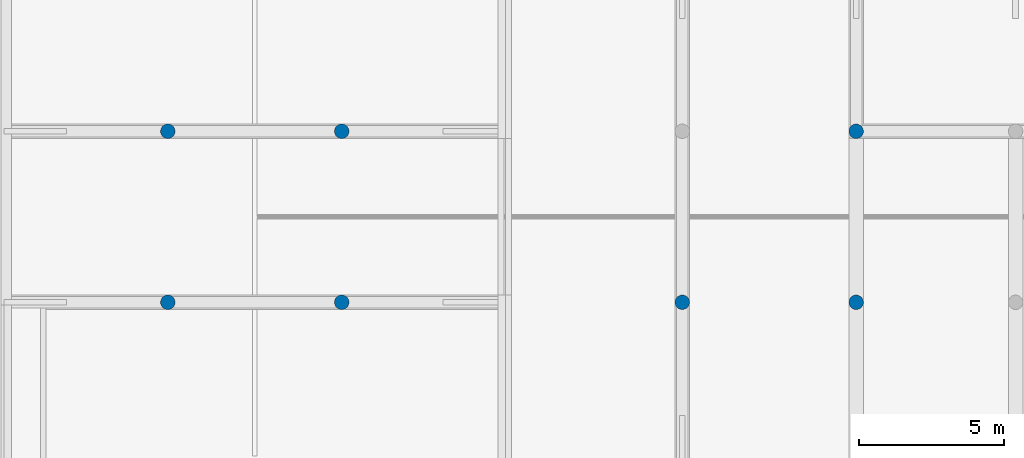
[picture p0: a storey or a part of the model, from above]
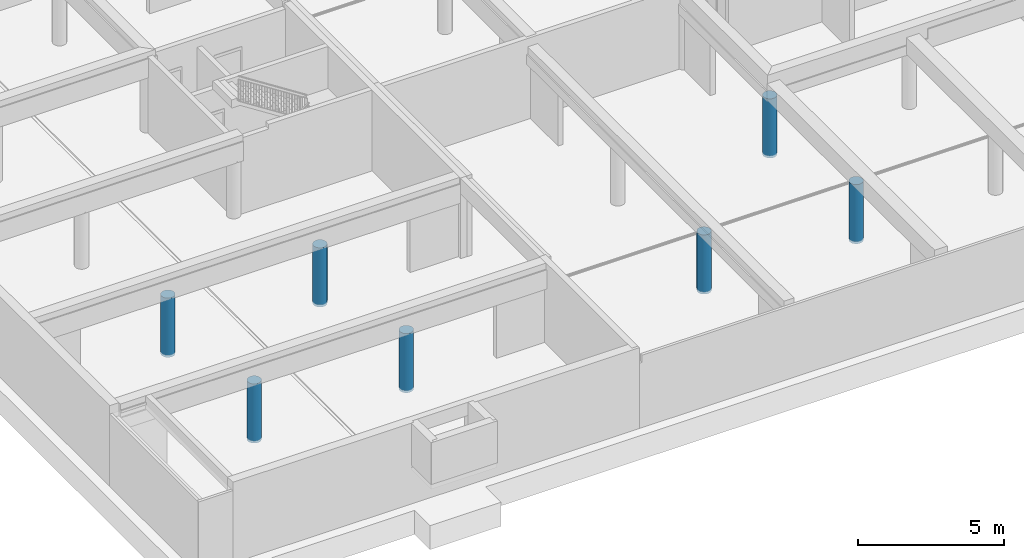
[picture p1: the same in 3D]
Properties of the parts of a building model (IFC2X3)

# File
Description: ViewDefinition [CoordinationView_V2.0], Option [Drawing Scale: 100.000000], Option [Elements to export: Visible elements (on all stories)], Option [Partial Structure Display: Entire Model], Option [IFC Domain: All], Option [Structural Function: All Elements], Option [Convert Grid elements: On], Option [Convert IFC Annotations and ARCHICAD 2D elements: Off], Option [Convert 2D symbols of Doors and Windows: Off], Option [Export geometries that Participates in Collision Detection only: Off], Option [Split complex elements: Off], Option [Material Preservation: Never explode], Option [Elements in Solid Element Operations: BRep], Option [Elements with junctions: BRep], Option [Slabs with slanted edge(s): BRep], Option [IFC Site Location: At Project Origin], Option [Curtain Wall export mode: Single Element], Option [Railing export mode: Single Element], Option [Stair export mode: Single Element], Option [Properties To Export: All properties], Option [Space containment: Off], Option [Bounding Box: Off], Option [Geometry to type objects: Off], Option [Element Properties: Off], Option [Building Material Properties: Off], Option [Element Parameters: Off], Option [Component Parameters: Off], Option [IFC Base Quantities: Off], Option [Door Window Parameters: On], Option [IFC Space boundaries: Off], Option [ARCHICAD Zone Categories as IFC Space classification data: Off], Option [Element Classifications: Off]
File name: C:\PROJEKTY\USTRONIE MORSKIE - Kulawiak\branze\09. Makieta\USTRONIE_7.1.ifc
Time: 2024-12-30T13:26:26
Author: mgr inż. arch. Mirosław Zwolski upr. nr BK IIF 7342/50/94
Organization: Building Designer Office
Written by: The EXPRESS Data Manager Version 5.02.0100.09 : 26 Sep 2013
Made in: IFC file generated by GRAPHISOFT ARCHICAD 23.0.0 POL FULL Windows version (IFC add-on version: 7000 POL FULL).
Authorization: mgr inż. arch. Mirosław Zwolski upr. nr BK IIF 7342/50/94

# IfcProject, BUDYNEK USŁUG TURYSTYCZNYCH
Description: BUDYNEK USŁUG TURYSTYCZNYCH WRAZ Z ZEWNĘTRZNĄ INSTALACJĄ GAZU, WEWNĘTRZNĄ LINIĄ ZASILANIA, INSTALACJĄ KANALIZACJI DESZCZOWEJ ORAZ PRZYŁĄCZAMI WODOCIĄGOWYM, KANALIZACJI SANITARNEJ I DESZCZOWEJ

# IfcSite, USTRONIE MORSKIE
Description: ul. NADBRZEŻNA 1 78-111 USTRONIE MORSKIE; RefLatitude: 54, 22, 0, 0; RefLongitude: 18, 40, 0, 0; RefElevation: 4500 mm

# IfcBuildingStorey (8)
In: Budynek
Name | Elevation (mm)
GARAZ | -3600
PARTER | 0
PIĘTRO 1 | 4000
PIĘTRO 2 | 7000
PIĘTRO 3 | 10000
PIĘTRO 4 | 13000
ANTRESOLA - KOND. TECHNICZNA | 16000
DACH | 19000

# IfcBeam: Beton konstrukcyjny 01 200 x 400 (3)
In: ANTRESOLA - KOND. TECHNICZNA
Material: Beton konstrukcyjny 01
Pset_BeamCommon - FireRating: -; Reference: Beton konstrukcyjny 01 200 x 400
Pset_ConcreteElementGeneral - FireRating: -; ConstructionType: -
Pset_FireRatingProperties - FireResistanceRating: -; IsCombustible: no
AC_Pset_RenovationAndPhasing - Renovation Status: New

# IfcBeam: Beton konstrukcyjny 01 200 x 500, B1
In: GARAZ
Material: Beton konstrukcyjny 01
Pset_BeamCommon - FireRating: -; Reference: Beton konstrukcyjny 01 200 x 500
Pset_ConcreteElementGeneral - FireRating: -; ConstructionType: -
Pset_FireRatingProperties - FireResistanceRating: -; IsCombustible: no
AC_Pset_RenovationAndPhasing - Renovation Status: New

# IfcBeam: Beton konstrukcyjny 01 200 x 550, B1
In: GARAZ
Material: Beton konstrukcyjny 01
Pset_BeamCommon - FireRating: -; Reference: Beton konstrukcyjny 01 200 x 550
Pset_ConcreteElementGeneral - FireRating: -; ConstructionType: -
Pset_FireRatingProperties - FireResistanceRating: -; IsCombustible: no
AC_Pset_RenovationAndPhasing - Renovation Status: New

# IfcBeam: Beton konstrukcyjny 01 200 x 650 (5)
In: GARAZ
Material: Beton konstrukcyjny 01
Pset_BeamCommon - FireRating: -; Reference: Beton konstrukcyjny 01 200 x 650
Pset_ConcreteElementGeneral - FireRating: -; ConstructionType: -
Pset_FireRatingProperties - FireResistanceRating: -; IsCombustible: no
AC_Pset_RenovationAndPhasing - Renovation Status: New

# IfcBeam: Beton konstrukcyjny 01 500 x 1000 (2)
In: GARAZ
Material: Beton konstrukcyjny 01
Pset_BeamCommon - FireRating: -; Reference: Beton konstrukcyjny 01 500 x 1000
Pset_ConcreteElementGeneral - FireRating: -; ConstructionType: -
Pset_FireRatingProperties - FireResistanceRating: -; IsCombustible: no
AC_Pset_RenovationAndPhasing - Renovation Status: New

# IfcBeam: Beton konstrukcyjny 01 500 x 700 (4)
In: GARAZ
Material: Beton konstrukcyjny 01
Pset_BeamCommon - FireRating: -; Reference: Beton konstrukcyjny 01 500 x 700
Pset_ConcreteElementGeneral - FireRating: -; ConstructionType: -
Pset_FireRatingProperties - FireResistanceRating: -; IsCombustible: no
AC_Pset_RenovationAndPhasing - Renovation Status: New

# IfcBeam: Beton konstrukcyjny B25 400 x 600 (2)
In: PARTER
Material: Beton konstrukcyjny B25
Pset_BeamCommon - FireRating: -; Reference: Beton konstrukcyjny B25 400 x 600
Pset_ConcreteElementGeneral - FireRating: -; ConstructionType: -
Pset_FireRatingProperties - FireResistanceRating: -; IsCombustible: no
AC_Pset_RenovationAndPhasing - Renovation Status: New

# IfcBeam: GARAŻ P01 500 x 1050 (20)
In: GARAZ
Material: Termoizolacja WEŁNA SKALNA, Beton konstrukcyjny 01
Pset_BeamCommon - FireRating: -; Reference: GARAŻ P01 500 x 1050
Pset_ConcreteElementGeneral - FireRating: -; ConstructionType: -
Pset_FireRatingProperties - FireResistanceRating: -; IsCombustible: no
AC_Pset_RenovationAndPhasing - Renovation Status: New

# IfcBeam: GARAŻ P02 500 x 700 (2)
In: GARAZ
Material: Termoizolacja WEŁNA SKALNA, Beton konstrukcyjny 01
Pset_BeamCommon - FireRating: -; Reference: GARAŻ P02 500 x 700
Pset_ConcreteElementGeneral - FireRating: -; ConstructionType: -
Pset_FireRatingProperties - FireResistanceRating: -; IsCombustible: no
AC_Pset_RenovationAndPhasing - Renovation Status: New

# IfcBeam: Laminat 50 x 250 (11)
In: DACH
Material: Laminat
Pset_BeamCommon - FireRating: -; Reference: Laminat 50 x 250
Pset_ConcreteElementGeneral - FireRating: -; ConstructionType: -
Pset_FireRatingProperties - FireResistanceRating: -; IsCombustible: no
AC_Pset_RenovationAndPhasing - Renovation Status: New

# IfcBeam: USTR - balkon_01 1850 x 570 (6)
In: PIĘTRO 1
Material: Laminat, Membrana przeciwwilgociowa, Blacha ocynkowana, Beton konstrukcyjny B25, Płyty styropianowe twarde HIGH-PRIORITY
Pset_BeamCommon - FireRating: -; Reference: USTR - balkon_01 1850 x 570
Pset_ConcreteElementGeneral - FireRating: -; ConstructionType: -
Pset_FireRatingProperties - FireResistanceRating: -; IsCombustible: no
AC_Pset_RenovationAndPhasing - Renovation Status: New
Name
3 x P7
3 x B1

# IfcBeam: USTR - balkon_02 1810 x 320 (18)
Material: Laminat, Membrana przeciwwilgociowa, Blacha ocynkowana, Beton konstrukcyjny B25, Płyty styropianowe twarde HIGH-PRIORITY
Pset_BeamCommon - FireRating: -; Reference: USTR - balkon_02 1810 x 320
Pset_ConcreteElementGeneral - FireRating: -; ConstructionType: -
Pset_FireRatingProperties - FireResistanceRating: -; IsCombustible: no
AC_Pset_RenovationAndPhasing - Renovation Status: New
Name | In
2 x B1 | PIĘTRO 2
4 x P8 | PIĘTRO 2
2 x B1 | PIĘTRO 3
4 x P8 | PIĘTRO 3
4 x P8 | PIĘTRO 4
2 x B1 | PIĘTRO 4

# IfcBeam: Własny Profil 50 x 250 (11)
In: DACH
Material: Laminat
Pset_BeamCommon - FireRating: -; Reference: Własny Profil 50 x 250
Pset_ConcreteElementGeneral - FireRating: -; ConstructionType: -
Pset_FireRatingProperties - FireResistanceRating: -; IsCombustible: no
AC_Pset_RenovationAndPhasing - Renovation Status: New

# IfcBuildingElementProxy (16)
AC_Pset_RenovationAndPhasing - Renovation Status: New
Name | In
Obiekt-007 | GARAZ
2 x Obiekt-007 | PARTER
2 x Obiekt-007 | PIĘTRO 1
2 x Obiekt-007 | PIĘTRO 2
2 x Obiekt-007 | PIĘTRO 3
2 x Obiekt-007 | PIĘTRO 4
2 x Obiekt-007 | ANTRESOLA - KOND. TECHNICZNA
3 x Obiekt-007 | DACH

# IfcBuildingElementProxy: 12+10 kominy 230 (163)
Pset_ConcreteElementGeneral - EnvironmentalClass: Brak
AC_Pset_RenovationAndPhasing - Renovation Status: New
Name | In | Material
2 x Œciana-006 | ANTRESOLA - KOND. TECHNICZNA | Bloczki silikatowe, Wełna ELEW, Tynk zewnętrzny
2 x Œciana-006 | ANTRESOLA - KOND. TECHNICZNA | Tynk zewnętrzny, Wełna ELEW, Bloczki silikatowe
86 x Œciana-006 | DACH | Bloczki silikatowe, Wełna ELEW, Tynk zewnętrzny
73 x Œciana-006 | DACH | Tynk zewnętrzny, Wełna ELEW, Bloczki silikatowe

# IfcBuildingElementProxy: 12+18_TERMO 310 (18)
Pset_ConcreteElementGeneral - EnvironmentalClass: Brak
AC_Pset_RenovationAndPhasing - Renovation Status: New
Name | In | Material
3 x Œciana-006 | ANTRESOLA - KOND. TECHNICZNA | Tynk zewnętrzny, Wełna ELEW, Bloczki silikatowe
3 x Œciana-006 | ANTRESOLA - KOND. TECHNICZNA | Bloczki silikatowe, Wełna ELEW, Tynk zewnętrzny
6 x Œciana-006 | DACH | Bloczki silikatowe, Wełna ELEW, Tynk zewnętrzny
6 x Œciana-006 | DACH | Tynk zewnętrzny, Wełna ELEW, Bloczki silikatowe

# IfcBuildingElementProxy: 12+20 330 (16)
Pset_ConcreteElementGeneral - EnvironmentalClass: Brak
AC_Pset_RenovationAndPhasing - Renovation Status: New
Name | In | Material
6 x Ściana-009 | ANTRESOLA - KOND. TECHNICZNA | Tynk zewnętrzny, Wełna ELEW, Bloczki silikatowe
6 x Ściana-009 | ANTRESOLA - KOND. TECHNICZNA | Bloczki silikatowe, Wełna ELEW, Tynk zewnętrzny
3 x Œciana-006 | DACH | Bloczki silikatowe, Wełna ELEW, Tynk zewnętrzny
Œciana-006 | DACH | Tynk zewnętrzny, Wełna ELEW, Bloczki silikatowe

# IfcBuildingElementProxy: 15+15 AKU 300, Œciana-007
In: ANTRESOLA - KOND. TECHNICZNA
Material: Wełna ELEW, Bloczki silikatowe
Pset_ConcreteElementGeneral - EnvironmentalClass: Brak
AC_Pset_RenovationAndPhasing - Renovation Status: New

# IfcBuildingElementProxy: 15+2xTYNK 170 (4)
In: ANTRESOLA - KOND. TECHNICZNA
Material: Tynk wewnętrzny (2), Beton konstrukcyjny B25
Pset_ConcreteElementGeneral - EnvironmentalClass: Brak
AC_Pset_RenovationAndPhasing - Renovation Status: New

# IfcBuildingElementProxy: 16+15 AKU 310 (7)
In: ANTRESOLA - KOND. TECHNICZNA
Pset_ConcreteElementGeneral - EnvironmentalClass: Brak
AC_Pset_RenovationAndPhasing - Renovation Status: New
Name | Material
Œciana-006 | Beton konstrukcyjny B25, Izolacja akustyczna
3 x Œciana-007 | Beton konstrukcyjny B25, Izolacja akustyczna
Œciana-006 | Izolacja akustyczna, Beton konstrukcyjny B25
2 x Œciana-007 | Izolacja akustyczna, Beton konstrukcyjny B25

# IfcBuildingElementProxy: 16+20 370 (2)
In: ANTRESOLA - KOND. TECHNICZNA
Pset_ConcreteElementGeneral - EnvironmentalClass: Brak
AC_Pset_RenovationAndPhasing - Renovation Status: New
Name | Material
SZ-01 | Tynk zewnętrzny, Wełna ELEW, Beton konstrukcyjny B25
SZ-01 | Beton konstrukcyjny B25, Wełna ELEW, Tynk zewnętrzny

# IfcBuildingElementProxy: 18 SILIKAT+-10 290 (7)
In: DACH
Pset_ConcreteElementGeneral - EnvironmentalClass: Brak
AC_Pset_RenovationAndPhasing - Renovation Status: New
Name | Material
4 x Œciana-006 | Tynk zewnętrzny, Wełna ELEW, Bloczki silikatowe
3 x Œciana-006 | Bloczki silikatowe, Wełna ELEW, Tynk zewnętrzny

# IfcBuildingElementProxy: 18 SILIKAT+20 390 (19)
In: DACH
Pset_ConcreteElementGeneral - EnvironmentalClass: Brak
AC_Pset_RenovationAndPhasing - Renovation Status: New
Name | Material
7 x Œciana-006 | Bloczki silikatowe, Wełna ELEW, Tynk zewnętrzny
10 x Œciana-006 | Tynk zewnętrzny, Wełna ELEW, Bloczki silikatowe
SZ-01 | Tynk zewnętrzny, Wełna ELEW, Bloczki silikatowe
SZ-01 | Bloczki silikatowe, Wełna ELEW, Tynk zewnętrzny

# IfcBuildingElementProxy: 18 SILIKAT+20-10 500 (47)
Material: Tynk zewnętrzny (2), Wełna ELEW (2), Bloczki silikatowe
Pset_ConcreteElementGeneral - EnvironmentalClass: Brak
AC_Pset_RenovationAndPhasing - Renovation Status: New
Name | In
14 x Œciana-006 | ANTRESOLA - KOND. TECHNICZNA
33 x Œciana-006 | DACH

# IfcBuildingElementProxy: 18 SILKA +5 AKU 255 (2)
In: PARTER
Pset_ConcreteElementGeneral - EnvironmentalClass: Brak
AC_Pset_RenovationAndPhasing - Renovation Status: New
Name | Material
SW-02 | Płyta GK, Izolacja akustyczna, Bloczki silikatowe
SW-02 | Bloczki silikatowe, Izolacja akustyczna, Płyta GK

# IfcBuildingElementProxy: 18+15 AKU 340 (16)
In: ANTRESOLA - KOND. TECHNICZNA
Pset_ConcreteElementGeneral - EnvironmentalClass: Brak
AC_Pset_RenovationAndPhasing - Renovation Status: New
Name | Material
7 x Œciana-006 | Tynk zewnętrzny, Wełna ELEW, Bloczki silikatowe
7 x Œciana-006 | Bloczki silikatowe, Wełna ELEW, Tynk zewnętrzny
2 x Œciana-007 | Tynk zewnętrzny, Wełna ELEW, Bloczki silikatowe

# IfcBuildingElementProxy: 20+10 300 (6)
Pset_ConcreteElementGeneral - EnvironmentalClass: Brak
AC_Pset_RenovationAndPhasing - Renovation Status: New
Name | In | Material
Œciana-006 | GARAZ | Płyty styropianowe twarde, Beton konstrukcyjny B25
Œciana-006 | PARTER | Płyty styropianowe twarde, Beton konstrukcyjny B25
Œciana-007 | DACH | Płyty styropianowe twarde, Beton konstrukcyjny B25
2 x Œciana-007 | DACH | Beton konstrukcyjny B25, Płyty styropianowe twarde
Œciana-008 | DACH | Płyty styropianowe twarde, Beton konstrukcyjny B25

# IfcBuildingElementProxy: 20+10 GARAŻ 310 (19)
Pset_ConcreteElementGeneral - EnvironmentalClass: Brak
AC_Pset_RenovationAndPhasing - Renovation Status: New
Name | In | Material
5 x Œciana-006 | GARAZ | Membrana przeciwwilgociowa, Płyty styropianowe twarde HIGH-PRIORITY, Beton konstrukcyjny 01
5 x Œciana-006 | GARAZ | Beton konstrukcyjny 01, Płyty styropianowe twarde HIGH-PRIORITY, Membrana przeciwwilgociowa
5 x Œciana-006 | PARTER | Beton konstrukcyjny 01, Płyty styropianowe twarde HIGH-PRIORITY, Membrana przeciwwilgociowa
4 x Œciana-006 | PARTER | Membrana przeciwwilgociowa, Płyty styropianowe twarde HIGH-PRIORITY, Beton konstrukcyjny 01

# IfcBuildingElementProxy: 20+15 360, SZ-02
In: PARTER
Material: Beton konstrukcyjny B25, Wełna ELEW, Tynk zewnętrzny
Pset_ConcreteElementGeneral - EnvironmentalClass: Brak
AC_Pset_RenovationAndPhasing - Renovation Status: New

# IfcBuildingElementProxy: 20+20 410 (160)
Pset_ConcreteElementGeneral - EnvironmentalClass: Brak
AC_Pset_RenovationAndPhasing - Renovation Status: New
Name | In | Material
SZ-01 | GARAZ | Beton konstrukcyjny B25, Wełna ELEW, Tynk zewnętrzny
17 x SZ-01 | PARTER | Beton konstrukcyjny B25, Wełna ELEW, Tynk zewnętrzny
5 x SZ-01 | PARTER | Tynk zewnętrzny, Wełna ELEW, Beton konstrukcyjny B25
13 x SZ-01 | PIĘTRO 1 | Beton konstrukcyjny B25, Wełna ELEW, Tynk zewnętrzny
11 x SZ-01 | PIĘTRO 1 | Tynk zewnętrzny, Wełna ELEW, Beton konstrukcyjny B25
11 x SZ-01 | PIĘTRO 2 | Tynk zewnętrzny, Wełna ELEW, Beton konstrukcyjny B25
14 x SZ-01 | PIĘTRO 2 | Beton konstrukcyjny B25, Wełna ELEW, Tynk zewnętrzny
13 x SZ-01 | PIĘTRO 3 | Beton konstrukcyjny B25, Wełna ELEW, Tynk zewnętrzny
11 x SZ-01 | PIĘTRO 3 | Tynk zewnętrzny, Wełna ELEW, Beton konstrukcyjny B25
13 x SZ-01 | PIĘTRO 4 | Beton konstrukcyjny B25, Wełna ELEW, Tynk zewnętrzny
11 x SZ-01 | PIĘTRO 4 | Tynk zewnętrzny, Wełna ELEW, Beton konstrukcyjny B25
9 x SZ-01 | ANTRESOLA - KOND. TECHNICZNA | Beton konstrukcyjny B25, Wełna ELEW, Tynk zewnętrzny
11 x SZ-01 | ANTRESOLA - KOND. TECHNICZNA | Tynk zewnętrzny, Wełna ELEW, Beton konstrukcyjny B25
6 x Œciana-006 | ANTRESOLA - KOND. TECHNICZNA | Beton konstrukcyjny B25, Wełna ELEW, Tynk zewnętrzny
5 x Œciana-006 | ANTRESOLA - KOND. TECHNICZNA | Tynk zewnętrzny, Wełna ELEW, Beton konstrukcyjny B25
Œciana-008 | ANTRESOLA - KOND. TECHNICZNA | Tynk zewnętrzny, Wełna ELEW, Beton konstrukcyjny B25
4 x Œciana-006 | DACH | Tynk zewnętrzny, Wełna ELEW, Beton konstrukcyjny B25
2 x SZ-01 | DACH | Tynk zewnętrzny, Wełna ELEW, Beton konstrukcyjny B25
2 x SZ-01 | DACH | Beton konstrukcyjny B25, Wełna ELEW, Tynk zewnętrzny

# IfcBuildingElementProxy: 20+20 HP 410 (4)
In: PARTER
Pset_ConcreteElementGeneral - EnvironmentalClass: Brak
AC_Pset_RenovationAndPhasing - Renovation Status: New
Name | Material
SZ-01 | Beton konstrukcyjny B25, Wełna ELEW wysoki priorytet, Tynk zewnętrzny
3 x SZ-01 | Tynk zewnętrzny, Wełna ELEW wysoki priorytet, Beton konstrukcyjny B25

# IfcBuildingElementProxy: 20+20-10 520 (2)
In: ANTRESOLA - KOND. TECHNICZNA
Material: Tynk zewnętrzny (2), Wełna ELEW (2), Beton konstrukcyjny B25
Pset_ConcreteElementGeneral - EnvironmentalClass: Brak
AC_Pset_RenovationAndPhasing - Renovation Status: New

# IfcBuildingElementProxy: 20+20-5 470 (6)
Material: Tynk zewnętrzny (2), Wełna ELEW (2), Beton konstrukcyjny B25
Pset_ConcreteElementGeneral - EnvironmentalClass: Brak
AC_Pset_RenovationAndPhasing - Renovation Status: New
Name | In
2 x Œciana-007 | PIĘTRO 4
2 x Œciana-006 | ANTRESOLA - KOND. TECHNICZNA
2 x Œciana-007 | ANTRESOLA - KOND. TECHNICZNA

# IfcBuildingElementProxy: 20+5 250 (8)
In: GARAZ
Pset_ConcreteElementGeneral - EnvironmentalClass: Brak
AC_Pset_RenovationAndPhasing - Renovation Status: New
Name | Material
2 x Œciana-008 | Płyty styropianowe twarde, Beton konstrukcyjny 01
Œciana-007 | Beton konstrukcyjny 01, Płyty styropianowe twarde
3 x Œciana-006 | Płyty styropianowe twarde, Beton konstrukcyjny 01
Œciana-007 | Płyty styropianowe twarde, Beton konstrukcyjny 01
SW-01 | Beton konstrukcyjny 01, Płyty styropianowe twarde

# IfcBuildingElementProxy: 20+5 AKU 275 (40)
Pset_ConcreteElementGeneral - EnvironmentalClass: Brak
AC_Pset_RenovationAndPhasing - Renovation Status: New
Name | In | Material
2 x SW-01 | PARTER | Beton konstrukcyjny B25, Izolacja akustyczna, Płyta GK
2 x SW-01 | PARTER | Płyta GK, Izolacja akustyczna, Beton konstrukcyjny B25
Œciana-007 | PARTER | Płyta GK, Izolacja akustyczna, Beton konstrukcyjny B25
Œciana-007 | PARTER | Beton konstrukcyjny B25, Izolacja akustyczna, Płyta GK
SW-01 | PIĘTRO 1 | Płyta GK, Izolacja akustyczna, Beton konstrukcyjny B25
3 x Œciana-007 | PIĘTRO 1 | Beton konstrukcyjny B25, Izolacja akustyczna, Płyta GK
SW-01 | PIĘTRO 1 | Beton konstrukcyjny B25, Izolacja akustyczna, Płyta GK
2 x Œciana-007 | PIĘTRO 1 | Płyta GK, Izolacja akustyczna, Beton konstrukcyjny B25
2 x Œciana-007 | PIĘTRO 2 | Płyta GK, Izolacja akustyczna, Beton konstrukcyjny B25
3 x Œciana-007 | PIĘTRO 2 | Beton konstrukcyjny B25, Izolacja akustyczna, Płyta GK
SW-01 | PIĘTRO 2 | Beton konstrukcyjny B25, Izolacja akustyczna, Płyta GK
SW-01 | PIĘTRO 2 | Płyta GK, Izolacja akustyczna, Beton konstrukcyjny B25
3 x Œciana-007 | PIĘTRO 3 | Beton konstrukcyjny B25, Izolacja akustyczna, Płyta GK
2 x Œciana-007 | PIĘTRO 3 | Płyta GK, Izolacja akustyczna, Beton konstrukcyjny B25
SW-01 | PIĘTRO 3 | Beton konstrukcyjny B25, Izolacja akustyczna, Płyta GK
SW-01 | PIĘTRO 3 | Płyta GK, Izolacja akustyczna, Beton konstrukcyjny B25
SW-01 | PIĘTRO 4 | Płyta GK, Izolacja akustyczna, Beton konstrukcyjny B25
3 x Œciana-007 | PIĘTRO 4 | Beton konstrukcyjny B25, Izolacja akustyczna, Płyta GK
2 x Œciana-007 | PIĘTRO 4 | Płyta GK, Izolacja akustyczna, Beton konstrukcyjny B25
SW-01 | PIĘTRO 4 | Beton konstrukcyjny B25, Izolacja akustyczna, Płyta GK
2 x SW-01 | ANTRESOLA - KOND. TECHNICZNA | Beton konstrukcyjny B25, Izolacja akustyczna, Płyta GK
Œciana-007 | ANTRESOLA - KOND. TECHNICZNA | Beton konstrukcyjny B25, Izolacja akustyczna, Płyta GK
2 x SW-01 | ANTRESOLA - KOND. TECHNICZNA | Płyta GK, Izolacja akustyczna, Beton konstrukcyjny B25
Œciana-006 | ANTRESOLA - KOND. TECHNICZNA | Płyta GK, Izolacja akustyczna, Beton konstrukcyjny B25

# IfcBuildingElementProxy: 20+8+2 320 (4)
In: PARTER
Pset_ConcreteElementGeneral - EnvironmentalClass: Brak
AC_Pset_RenovationAndPhasing - Renovation Status: New
Name | Material
3 x Œciana-006 | Laminat, Płyty styropianowe twarde, Beton konstrukcyjny B25
Œciana-006 | Beton konstrukcyjny B25, Płyty styropianowe twarde, Laminat

# IfcBuildingElementProxy: 25+10 GARAŻ 360 (13)
In: GARAZ
Pset_ConcreteElementGeneral - EnvironmentalClass: Brak
AC_Pset_RenovationAndPhasing - Renovation Status: New
Name | Material
6 x SZ-02 | Beton konstrukcyjny 01, Płyty styropianowe twarde HIGH-PRIORITY, Membrana przeciwwilgociowa
7 x SZ-02 | Membrana przeciwwilgociowa, Płyty styropianowe twarde HIGH-PRIORITY, Beton konstrukcyjny 01

# IfcBuildingElementProxy: 330-SD GK 2-warstwy 75 (299)
Pset_ConcreteElementGeneral - EnvironmentalClass: Brak
AC_Pset_RenovationAndPhasing - Renovation Status: New
Name | In | Material
29 x Ściana-009 | PARTER | Płyta GK (2), -Pustka powietrzna
22 x Ściana-009 | PARTER | -Pustka powietrzna, Płyta GK (2)
32 x Ściana-009 | PIĘTRO 1 | -Pustka powietrzna, Płyta GK (2)
32 x Ściana-009 | PIĘTRO 1 | Płyta GK (2), -Pustka powietrzna
32 x Ściana-009 | PIĘTRO 2 | -Pustka powietrzna, Płyta GK (2)
32 x Ściana-009 | PIĘTRO 2 | Płyta GK (2), -Pustka powietrzna
30 x Ściana-009 | PIĘTRO 3 | Płyta GK (2), -Pustka powietrzna
32 x Ściana-009 | PIĘTRO 3 | -Pustka powietrzna, Płyta GK (2)
29 x Ściana-009 | PIĘTRO 4 | Płyta GK (2), -Pustka powietrzna
29 x Ściana-009 | PIĘTRO 4 | -Pustka powietrzna, Płyta GK (2)

# IfcBuildingElementProxy: BALKON bok 01 520 (52)
Material: Tynk zewnętrzny (2), Wełna ELEW (2), Beton konstrukcyjny B25
Pset_ConcreteElementGeneral - EnvironmentalClass: Brak
AC_Pset_RenovationAndPhasing - Renovation Status: New
Name | In
12 x Œciana-006 | PIĘTRO 1
12 x Œciana-006 | PIĘTRO 2
12 x Œciana-006 | PIĘTRO 3
12 x Œciana-006 | PIĘTRO 4
2 x Œciana-007 | ANTRESOLA - KOND. TECHNICZNA
2 x Œciana-006 | ANTRESOLA - KOND. TECHNICZNA

# IfcBuildingElementProxy: BALKON bok 04 220 (4)
In: ANTRESOLA - KOND. TECHNICZNA
Material: Tynk zewnętrzny (2), Bloczki silikatowe
Pset_ConcreteElementGeneral - EnvironmentalClass: Brak
AC_Pset_RenovationAndPhasing - Renovation Status: New

# IfcBuildingElementProxy: Beton konstrukcyjny 01 200 (71)
In: GARAZ
Material: Beton konstrukcyjny 01
Pset_ConcreteElementGeneral - EnvironmentalClass: Brak
AC_Pset_RenovationAndPhasing - Renovation Status: New
Name
68 x SW-01
2 x SW-02
Œciana-007

# IfcBuildingElementProxy: Beton konstrukcyjny 01 250, Œciana-008
In: GARAZ
Material: Beton konstrukcyjny 01
Pset_ConcreteElementGeneral - EnvironmentalClass: Brak
AC_Pset_RenovationAndPhasing - Renovation Status: New

# IfcBuildingElementProxy: Beton konstrukcyjny B25 160 (86)
Material: Beton konstrukcyjny B25
Pset_ConcreteElementGeneral - EnvironmentalClass: Brak
AC_Pset_RenovationAndPhasing - Renovation Status: New
Name | In
19 x SW-01 | PARTER
16 x SW-01 | PIĘTRO 1
16 x SW-01 | PIĘTRO 2
16 x SW-01 | PIĘTRO 3
13 x SW-01 | PIĘTRO 4
5 x SW-01 | ANTRESOLA - KOND. TECHNICZNA
SZ-01 | ANTRESOLA - KOND. TECHNICZNA

# IfcBuildingElementProxy: Beton konstrukcyjny B25 180, SW-01
In: ANTRESOLA - KOND. TECHNICZNA
Material: Beton konstrukcyjny B25
Pset_ConcreteElementGeneral - EnvironmentalClass: Brak
AC_Pset_RenovationAndPhasing - Renovation Status: New

# IfcBuildingElementProxy: Beton konstrukcyjny B25 200 (401)
Material: Beton konstrukcyjny B25
Pset_ConcreteElementGeneral - EnvironmentalClass: Brak
AC_Pset_RenovationAndPhasing - Renovation Status: New
Name | In
71 x SW-01 | PARTER
71 x SW-01 | PIĘTRO 1
71 x SW-01 | PIĘTRO 2
67 x SW-01 | PIĘTRO 3
68 x SW-01 | PIĘTRO 4
47 x SW-01 | ANTRESOLA - KOND. TECHNICZNA
Œciana-006 | ANTRESOLA - KOND. TECHNICZNA
2 x SZ-01 | ANTRESOLA - KOND. TECHNICZNA
3 x SW-01 | DACH

# IfcBuildingElementProxy: Beton konstrukcyjny B25 450 (2)
In: ANTRESOLA - KOND. TECHNICZNA
Material: Beton konstrukcyjny B25
Pset_ConcreteElementGeneral - EnvironmentalClass: Brak
AC_Pset_RenovationAndPhasing - Renovation Status: New

# IfcBuildingElementProxy: Bloczki silikatowe 120 (796)
Material: Bloczki silikatowe
Pset_ConcreteElementGeneral - EnvironmentalClass: Brak
AC_Pset_RenovationAndPhasing - Renovation Status: New
Name | In
3 x SW-04 | GARAZ
126 x SW-04 | PARTER
9 x Ściana-010 | PARTER
2 x Œciana-007 | PARTER
148 x SW-04 | PIĘTRO 1
148 x SW-04 | PIĘTRO 2
150 x SW-04 | PIĘTRO 3
140 x SW-04 | PIĘTRO 4
4 x Ściana-009 | PIĘTRO 4
62 x SW-04 | ANTRESOLA - KOND. TECHNICZNA
4 x Ściana-009 | ANTRESOLA - KOND. TECHNICZNA

# IfcBuildingElementProxy: Bloczki silikatowe 150 (633)
Material: Bloczki silikatowe
Pset_ConcreteElementGeneral - EnvironmentalClass: Brak
AC_Pset_RenovationAndPhasing - Renovation Status: New
Name | In
12 x SW-04 | PARTER
48 x SW-03 | PARTER
22 x Ściana-009 | PARTER
6 x Œciana-007 | PARTER
28 x Ściana-009 | PIĘTRO 1
67 x SW-03 | PIĘTRO 1
10 x SW-04 | PIĘTRO 1
4 x Œciana-007 | PIĘTRO 1
71 x SW-03 | PIĘTRO 2
10 x SW-04 | PIĘTRO 2
24 x Ściana-009 | PIĘTRO 2
4 x Œciana-007 | PIĘTRO 2
101 x SW-03 | PIĘTRO 3
8 x Ściana-009 | PIĘTRO 3
4 x Ściana-010 | PIĘTRO 3
4 x Œciana-007 | PIĘTRO 3
117 x SW-03 | PIĘTRO 4
4 x Ściana-009 | PIĘTRO 4
4 x Œciana-007 | PIĘTRO 4
78 x SW-03 | ANTRESOLA - KOND. TECHNICZNA
5 x SW-04 | ANTRESOLA - KOND. TECHNICZNA
2 x SW-02 | ANTRESOLA - KOND. TECHNICZNA

# IfcBuildingElementProxy: Bloczki silikatowe 180 (137)
Material: Bloczki silikatowe
Pset_ConcreteElementGeneral - EnvironmentalClass: Brak
AC_Pset_RenovationAndPhasing - Renovation Status: New
Name | In
18 x SW-02 | PARTER
23 x SW-02 | PIĘTRO 1
24 x SW-02 | PIĘTRO 2
21 x SW-02 | PIĘTRO 3
18 x SW-02 | PIĘTRO 4
2 x Œciana-007 | PIĘTRO 4
29 x SW-02 | ANTRESOLA - KOND. TECHNICZNA
2 x Œciana-006 | ANTRESOLA - KOND. TECHNICZNA

# IfcBuildingElementProxy: Bloczki silikatowe 200 (6)
Material: Bloczki silikatowe
Pset_ConcreteElementGeneral - EnvironmentalClass: Brak
AC_Pset_RenovationAndPhasing - Renovation Status: New
Name | In
2 x SW-01 | PARTER
4 x SW-01 | ANTRESOLA - KOND. TECHNICZNA

# IfcBuildingElementProxy: Bloczki silikatowe 240, Œciana-006
In: PARTER
Material: Bloczki silikatowe
Pset_ConcreteElementGeneral - EnvironmentalClass: Brak
AC_Pset_RenovationAndPhasing - Renovation Status: New

# IfcBuildingElementProxy: Bloczki silikatowe 40 (2)
In: PARTER
Material: Bloczki silikatowe
Pset_ConcreteElementGeneral - EnvironmentalClass: Brak
AC_Pset_RenovationAndPhasing - Renovation Status: New

# IfcBuildingElementProxy: Bloczki silikatowe 80 (152)
Material: Bloczki silikatowe
Pset_ConcreteElementGeneral - EnvironmentalClass: Brak
AC_Pset_RenovationAndPhasing - Renovation Status: New
Name | In
12 x Ściana-010 | PARTER
12 x Ściana-009 | PARTER
8 x Œciana-007 | PARTER
16 x Ściana-010 | PIĘTRO 1
14 x Ściana-009 | PIĘTRO 1
14 x Ściana-009 | PIĘTRO 2
16 x Ściana-010 | PIĘTRO 2
13 x Ściana-009 | PIĘTRO 3
15 x Ściana-010 | PIĘTRO 3
2 x Œciana-007 | PIĘTRO 3
14 x Ściana-009 | PIĘTRO 4
16 x Ściana-010 | PIĘTRO 4

# IfcBuildingElementProxy: Drzwi 23 (531)
Pset_ConcreteElementGeneral - EnvironmentalClass: Brak
Pset_PrecastConcreteElementGeneral - SerialNumber: -
Pset_ManufacturerOccurrence - BarCode: -
Pset_ManufacturerTypeInformation - ModelLabel: -
AC_Pset_RenovationAndPhasing - Renovation Status: New
Name | In | FireRating = FireResistanceRating
4 x Dw01 | GARAZ | EI 30
6 x Dw02 | GARAZ | EI 60
3 x Dw03 | GARAZ | EI 30
30 x Dw.1 | PARTER | EI 30
33 x Dw.4 | PARTER | nd.
18 x Dw.3 | PARTER | nd
7 x Dw.2 | PARTER | EI 60
Dw.4' | PARTER | nd.
Dw.1' | PARTER | EIS 30
2 x Dw.2S | PARTER | EIS 60
 | PARTER
Syst. | PARTER
37 x Dw.4 | PIĘTRO 1 | nd.
24 x Dw.3 | PIĘTRO 1 | nd
38 x Dw.1 | PIĘTRO 1 | EI 30
7 x Dw.2 | PIĘTRO 1 | EI 60
Dw.4' | PIĘTRO 1 | nd.
Dw.1' | PIĘTRO 1 | EIS 30
37 x Dw.4 | PIĘTRO 2 | nd.
38 x Dw.1 | PIĘTRO 2 | EI 30
24 x Dw.3 | PIĘTRO 2 | nd
7 x Dw.2 | PIĘTRO 2 | EI 60
Dw.4' | PIĘTRO 2 | nd.
Dw.1' | PIĘTRO 2 | EIS 30
35 x Dw.4 | PIĘTRO 3 | nd.
36 x Dw.1 | PIĘTRO 3 | EI 30
30 x Dw.3 | PIĘTRO 3 | nd
Dw.1' | PIĘTRO 3 | EIS 30
7 x Dw.2 | PIĘTRO 3 | EI 60
Dw.4' | PIĘTRO 3 | nd.
36 x Dw.4 | PIĘTRO 4 | nd.
9 x Dw.3 | PIĘTRO 4 | nd
5 x Dw.2 | PIĘTRO 4 | EI 60
36 x Dw.1 | PIĘTRO 4 | EI 30
3 x Dw.03 | PIĘTRO 4
Dw.1' | PIĘTRO 4 | EIS 30
2 x  | ANTRESOLA - KOND. TECHNICZNA | EIS 60
2 x D8 | ANTRESOLA - KOND. TECHNICZNA | EI 60
Dw.01 | ANTRESOLA - KOND. TECHNICZNA | EIS 30
2 x Dw.02 | ANTRESOLA - KOND. TECHNICZNA | EI 30
D9 | ANTRESOLA - KOND. TECHNICZNA | EI 60

# IfcBuildingElementProxy: Drzwi garażowe, segmentowe 23, B01
In: GARAZ
Pset_ConcreteElementGeneral - EnvironmentalClass: Brak
Pset_PrecastConcreteElementGeneral - SerialNumber: -
Pset_ManufacturerOccurrence - BarCode: -
Pset_ManufacturerTypeInformation - ModelLabel: -
AC_Pset_RenovationAndPhasing - Renovation Status: New

# IfcBuildingElementProxy: Drzwi podwójne 23 (62)
Pset_ConcreteElementGeneral - EnvironmentalClass: Brak
Pset_PrecastConcreteElementGeneral - SerialNumber: -
Pset_ManufacturerOccurrence - BarCode: -
Pset_ManufacturerTypeInformation - ModelLabel: -
AC_Pset_RenovationAndPhasing - Renovation Status: New
Name | In | FireRating = FireResistanceRating
3 x D2 | PARTER | EIS 30
2 x Dw.5 | PARTER | EI 30
2 x Dw.6s | PARTER | EIS 60
2 x Dw.6 | PARTER | EI 30
D3 | PARTER | EI 60
2 x D5 | PARTER
2 x Dw.5s | PARTER | EIS 60
Dw5 | PARTER | EIS 60
Dw5 | PARTER
Dw5 | PARTER | EI 30
3 x Dw.6s | PIĘTRO 1 | EIS 60
2 x Dw.6 | PIĘTRO 1 | EI 30
2 x Dw.5s | PIĘTRO 1 | EIS 60
2 x Dw.5 | PIĘTRO 1 | EI 30
2 x D2 | PIĘTRO 1 | EIS 30
2 x D2 | PIĘTRO 2 | EIS 30
2 x Dw.6 | PIĘTRO 2 | EI 30
2 x Dw.5s | PIĘTRO 2 | EIS 60
Dw5 | PIĘTRO 2 | EIS 60
2 x Dw.5 | PIĘTRO 2 | EI 30
2 x Dw.6s | PIĘTRO 2 | EIS 60
2 x Dw.6s | PIĘTRO 3 | EIS 60
2 x D2 | PIĘTRO 3 | EIS 30
2 x Dw.6 | PIĘTRO 3 | EI 30
2 x Dw.5 | PIĘTRO 3 | EI 30
2 x Dw.5s | PIĘTRO 3 | EIS 60
Dw5 | PIĘTRO 3 | EIS 60
2 x Dw.6 | PIĘTRO 4 | EI 30
Dw5 | PIĘTRO 4 | EIS 60
2 x Dw.5 | PIĘTRO 4 | EI 30
2 x Dw.5s | PIĘTRO 4 | EIS 60
2 x Dw.6s | PIĘTRO 4 | EIS 60
D2 | PIĘTRO 4 | EIS 30
Dw.111 | PIĘTRO 4 | EIS 30
D9 | ANTRESOLA - KOND. TECHNICZNA | EI 30

# IfcBuildingElementProxy: Drzwi podwójne, przesuwne 23 (2)
In: PARTER
Pset_ConcreteElementGeneral - EnvironmentalClass: Brak
Pset_PrecastConcreteElementGeneral - SerialNumber: -
Pset_ManufacturerOccurrence - BarCode: -
Pset_ManufacturerTypeInformation - ModelLabel: -
AC_Pset_RenovationAndPhasing - Renovation Status: New

# IfcBuildingElementProxy: Drzwi przesuwne 23 (8)
Pset_ConcreteElementGeneral - EnvironmentalClass: Brak
Pset_PrecastConcreteElementGeneral - SerialNumber: -
Pset_ManufacturerOccurrence - BarCode: -
Pset_ManufacturerTypeInformation - ModelLabel: -
AC_Pset_RenovationAndPhasing - Renovation Status: New
Name | In
2 x D-WC | PIĘTRO 1
2 x D-WC | PIĘTRO 2
2 x D-WC | PIĘTRO 3
2 x D-WC | PIĘTRO 4

# IfcBuildingElementProxy: Laminat 150 (48)
Material: Laminat
Pset_ConcreteElementGeneral - EnvironmentalClass: Brak
AC_Pset_RenovationAndPhasing - Renovation Status: New
Name | In
12 x  | PIĘTRO 1
12 x SW-03 | PIĘTRO 2
12 x SW-03 | PIĘTRO 3
12 x SW-03 | PIĘTRO 4

# IfcBuildingElementProxy: Laminat 20 (8)
In: PARTER
Material: Laminat
Pset_ConcreteElementGeneral - EnvironmentalClass: Brak
AC_Pset_RenovationAndPhasing - Renovation Status: New

# IfcBuildingElementProxy: Laminat 80 (4)
In: ANTRESOLA - KOND. TECHNICZNA
Material: Laminat
Pset_ConcreteElementGeneral - EnvironmentalClass: Brak
AC_Pset_RenovationAndPhasing - Renovation Status: New

# IfcBuildingElementProxy: Okno 23 (6)
Pset_ConcreteElementGeneral - EnvironmentalClass: Brak
Pset_PrecastConcreteElementGeneral - SerialNumber: -
Pset_ManufacturerOccurrence - BarCode: -
Pset_ManufacturerTypeInformation - ModelLabel: -
AC_Pset_RenovationAndPhasing - Renovation Status: New
Name | In
4 x Okna-005 | PARTER
2 x Wz.04 | PIĘTRO 4

# IfcBuildingElementProxy: Okno podwójne 23 (241)
Pset_ConcreteElementGeneral - EnvironmentalClass: Brak
Pset_PrecastConcreteElementGeneral - SerialNumber: -
Pset_ManufacturerOccurrence - BarCode: -
Pset_ManufacturerTypeInformation - ModelLabel: -
AC_Pset_RenovationAndPhasing - Renovation Status: New
Name | In
36 x Wz.05 | PARTER
3 x Wz.01 | PARTER
5 x Wz.02 | PARTER
Wz.03 | PARTER
5 x Wz.02 | PIĘTRO 1
4 x Wz.01 | PIĘTRO 1
46 x Wz.05 | PIĘTRO 1
Wz.03 | PIĘTRO 1
46 x Wz.05 | PIĘTRO 2
6 x Wz.02 | PIĘTRO 2
4 x Wz.01 | PIĘTRO 2
4 x Wz.01 | PIĘTRO 3
48 x Wz.05 | PIĘTRO 3
6 x Wz.02 | PIĘTRO 3
6 x Wz.02 | PIĘTRO 4
2 x Wz.01 | PIĘTRO 4
16 x Wz.05 | PIĘTRO 4
2 x Wz.01 | ANTRESOLA - KOND. TECHNICZNA

# IfcBuildingElementProxy: Okno potrójne 23 (53)
Pset_ConcreteElementGeneral - EnvironmentalClass: Brak
Pset_PrecastConcreteElementGeneral - SerialNumber: -
Pset_ManufacturerOccurrence - BarCode: -
Pset_ManufacturerTypeInformation - ModelLabel: -
AC_Pset_RenovationAndPhasing - Renovation Status: New
Name | In
2 x Okna-004 | PARTER
2 x Wz.04 | PARTER | Pset_ConcreteElementGeneral - FireRating: EI 60; Pset_FireRatingProperties - FireResistanceRating: EI 60
3 x Wz.06 | PARTER
6 x Wz.06 | PIĘTRO 1
6 x Wz.06 | PIĘTRO 2
6 x Wz.06 | PIĘTRO 3
6 x Wz.06 | PIĘTRO 4
22 x Wz.06 | ANTRESOLA - KOND. TECHNICZNA

# IfcBuildingElementProxy: Okno poziome wieloskrzydłowe 23 (18)
Pset_ConcreteElementGeneral - EnvironmentalClass: Brak
Pset_PrecastConcreteElementGeneral - SerialNumber: -
Pset_ManufacturerOccurrence - BarCode: -
Pset_ManufacturerTypeInformation - ModelLabel: -
AC_Pset_RenovationAndPhasing - Renovation Status: New
Name | In
16 x Wz.05 | PIĘTRO 4
2 x Wz.05 | ANTRESOLA - KOND. TECHNICZNA

# IfcBuildingElementProxy: Okno połaciowe 23 (5)
In: DACH
Pset_ConcreteElementGeneral - EnvironmentalClass: Brak
Pset_PrecastConcreteElementGeneral - SerialNumber: -
Pset_ManufacturerOccurrence - BarCode: -
Pset_ManufacturerTypeInformation - ModelLabel: -
AC_Pset_RenovationAndPhasing - Renovation Status: New

# IfcBuildingElementProxy: Okno przesuwne, 2-skrzydłowe 23 (22)
Pset_ConcreteElementGeneral - EnvironmentalClass: Brak
Pset_PrecastConcreteElementGeneral - SerialNumber: -
Pset_ManufacturerOccurrence - BarCode: -
Pset_ManufacturerTypeInformation - ModelLabel: -
AC_Pset_RenovationAndPhasing - Renovation Status: New
Name | In
2 x Wz.04 | PARTER
4 x Wz.04 | PIĘTRO 1
4 x Wz.04 | PIĘTRO 2
4 x Wz.04 | PIĘTRO 3
4 x Wz.04 | PIĘTRO 4
4 x Wz.04 | ANTRESOLA - KOND. TECHNICZNA

# IfcBuildingElementProxy: Skrzynka P-Poż 23 (57)
AC_Pset_RenovationAndPhasing - Renovation Status: New
Name | In
3 x OB3 | GARAZ
11 x OB3 | PARTER
10 x OB3 | PIĘTRO 1
10 x OB3 | PIĘTRO 2
10 x OB3 | PIĘTRO 3
10 x OB3 | PIĘTRO 4
3 x OB3 | ANTRESOLA - KOND. TECHNICZNA

# IfcBuildingElementProxy: Typ schodów (18)
AC_Pset_RenovationAndPhasing - Renovation Status: New
Name | In | Material
3 x SCH2 | GARAZ | Beton konstrukcyjny B25 (3), Płytki podłogowe (19)
3 x SCH2 | PARTER | Beton konstrukcyjny B25 (3), Płytki podłogowe (22)
3 x SCH2 | PIĘTRO 1 | Beton konstrukcyjny B25 (3), Płytki podłogowe (17)
3 x SCH2 | PIĘTRO 2 | Beton konstrukcyjny B25 (3), Płytki podłogowe (17)
3 x SCH2 | PIĘTRO 3 | Beton konstrukcyjny B25 (3), Płytki podłogowe (17)
2 x SCH2 | PIĘTRO 4 | Beton konstrukcyjny B25 (3), Płytki podłogowe (16)
SCH2 | PIĘTRO 4 | Beton konstrukcyjny B25 (3), Płytki podłogowe (17)

# IfcBuildingElementProxy: Witryna sklepowa 23 (5)
Pset_ConcreteElementGeneral - EnvironmentalClass: Brak
Pset_PrecastConcreteElementGeneral - SerialNumber: Wył.-
Pset_ManufacturerOccurrence - BarCode: -; SerialNumber: Wył.
Pset_ManufacturerTypeInformation - ModelLabel: -
AC_Pset_RenovationAndPhasing - Renovation Status: New
Name | In
4 x Wz.04 | ANTRESOLA - KOND. TECHNICZNA
Wz.06 | DACH

# IfcBuildingElementProxy: Witryna sklepowa, naświetle 2 23 (4)
In: PIĘTRO 4
Pset_ConcreteElementGeneral - EnvironmentalClass: Brak
Pset_PrecastConcreteElementGeneral - SerialNumber: Wył.-
Pset_ManufacturerOccurrence - BarCode: -; SerialNumber: Wył.
Pset_ManufacturerTypeInformation - ModelLabel: -
AC_Pset_RenovationAndPhasing - Renovation Status: New
Name
2 x Wz.05
2 x Wz.04

# IfcBuildingElementProxy: Woda 30 (96)
Material: Woda
Pset_ConcreteElementGeneral - EnvironmentalClass: Brak
AC_Pset_RenovationAndPhasing - Renovation Status: New
Name | In
8 x Œciana-007 | PARTER
22 x Œciana-007 | PIĘTRO 1
22 x Œciana-007 | PIĘTRO 2
22 x Œciana-007 | PIĘTRO 3
22 x Œciana-007 | PIĘTRO 4

# IfcColumn: ----PREFABRYKATY 400 x 400 (2)
In: PARTER
Material: ----PREFABRYKATY
Pset_ConcreteElementGeneral - FireRating: -; ConstructionType: -
Pset_FireRatingProperties - FireResistanceRating: -; IsCombustible: no
AC_Pset_RenovationAndPhasing - Renovation Status: New
Pset_ColumnCommon - Reference: ----PREFABRYKATY 400 x 400

# IfcColumn: ----PREFABRYKATY D400 (2)
In: PARTER
Material: ----PREFABRYKATY
Pset_ConcreteElementGeneral - FireRating: -; ConstructionType: -
Pset_FireRatingProperties - FireResistanceRating: -; IsCombustible: no
AC_Pset_RenovationAndPhasing - Renovation Status: New
Pset_ColumnCommon - Reference: ----PREFABRYKATY D400

# IfcColumn: Beton konstrukcyjny 01 200 x 200 (3)
In: ANTRESOLA - KOND. TECHNICZNA
Material: Beton konstrukcyjny 01
Pset_ConcreteElementGeneral - FireRating: -; ConstructionType: -
Pset_FireRatingProperties - FireResistanceRating: -; IsCombustible: no
AC_Pset_RenovationAndPhasing - Renovation Status: New
Pset_ColumnCommon - Reference: Beton konstrukcyjny 01 200 x 200

# IfcColumn: Beton konstrukcyjny 01 D500 (49)
In: GARAZ
Material: Beton konstrukcyjny 01
Pset_ConcreteElementGeneral - FireRating: -; ConstructionType: -
Pset_FireRatingProperties - FireResistanceRating: -; IsCombustible: no
AC_Pset_RenovationAndPhasing - Renovation Status: New
Pset_ColumnCommon - Reference: Beton konstrukcyjny 01 D500
Name
41 x S1
4 x S2
S4
3 x S3

# IfcColumn: Beton konstrukcyjny B25 200 x 200, S1
In: ANTRESOLA - KOND. TECHNICZNA
Material: Beton konstrukcyjny B25
Pset_ConcreteElementGeneral - FireRating: -; ConstructionType: -
Pset_FireRatingProperties - FireResistanceRating: -; IsCombustible: no
AC_Pset_RenovationAndPhasing - Renovation Status: New
Pset_ColumnCommon - Reference: Beton konstrukcyjny B25 200 x 200

# IfcRailing: Typ balustrady (179)
Pset_FireRatingProperties - IsCombustible: no
AC_Pset_RenovationAndPhasing - Renovation Status: New
Pset_RailingCommon - IsExternal: no
Name | In | Material
BL1 | GARAZ | Stal konstrukcyjna (21), Stal nierdzewna (3)
BL1 | GARAZ | Stal konstrukcyjna (27), Stal nierdzewna (3)
2 x BL1 | GARAZ | Stal konstrukcyjna (25), Stal nierdzewna (3)
2 x BL1 | GARAZ | Stal konstrukcyjna (20), Stal nierdzewna (3)
BL1 | GARAZ | Stal konstrukcyjna (5), Stal nierdzewna (3)
BL1 | PARTER | Szkło struktualne, Profile aluminiowe
2 x BL1 | PARTER | Szkło struktualne (3), Profile aluminiowe (3)
BL1 | PARTER | Szkło struktualne (2), Profile aluminiowe (2)
2 x BL1 | PARTER | Stal konstrukcyjna (25), Stal nierdzewna (3)
BL1 | PARTER | Stal konstrukcyjna (33), Stal nierdzewna (3)
BL1 | PARTER | Stal konstrukcyjna (27), Stal nierdzewna (3)
BL1 | PARTER | Stal konstrukcyjna (23), Stal nierdzewna (3)
BL1 | PARTER | Stal konstrukcyjna (29), Stal nierdzewna (3)
12 x BL1 | PIĘTRO 1 | Szkło struktualne, Profile aluminiowe
4 x BL1 | PIĘTRO 1 | Szkło struktualne (3), Profile aluminiowe (3)
2 x BL1 | PIĘTRO 1 | Stal nierdzewna (3)
2 x BL1 | PIĘTRO 1 | Szkło struktualne (2), Profile aluminiowe (2)
BL1 | PIĘTRO 1 | Stal konstrukcyjna (28), Stal nierdzewna (6)
BL1 | PIĘTRO 1 | Stal konstrukcyjna (9), Stal nierdzewna (3)
2 x BL1 | PIĘTRO 1 | Stal konstrukcyjna (20), Stal nierdzewna (3)
2 x BL1 | PIĘTRO 1 | Stal konstrukcyjna (8), Stal nierdzewna (3)
BL1 | PIĘTRO 1 | Stal konstrukcyjna (23), Stal nierdzewna (3)
BL1 | PIĘTRO 1 | Stal konstrukcyjna (18), Stal nierdzewna (3)
12 x BL1 | PIĘTRO 2 | Szkło struktualne, Profile aluminiowe
4 x BL1 | PIĘTRO 2 | Szkło struktualne (3), Profile aluminiowe (3)
2 x BL1 | PIĘTRO 2 | Stal nierdzewna (3)
2 x BL1 | PIĘTRO 2 | Szkło struktualne (2), Profile aluminiowe (2)
BL1 | PIĘTRO 2 | Stal konstrukcyjna (29), Stal nierdzewna (9)
BL1 | PIĘTRO 2 | Stal konstrukcyjna (28), Stal nierdzewna (6)
2 x BL1 | PIĘTRO 2 | Stal konstrukcyjna (20), Stal nierdzewna (3)
BL1 | PIĘTRO 2 | Stal konstrukcyjna (23), Stal nierdzewna (3)
BL1 | PIĘTRO 2 | Stal konstrukcyjna (18), Stal nierdzewna (3)
12 x BL1 | PIĘTRO 3 | Szkło struktualne, Profile aluminiowe
4 x BL1 | PIĘTRO 3 | Szkło struktualne (3), Profile aluminiowe (3)
2 x BL1 | PIĘTRO 3 | Szkło struktualne (2), Profile aluminiowe (2)
2 x BL1 | PIĘTRO 3 | Stal nierdzewna (3)
BL1 | PIĘTRO 3 | Stal konstrukcyjna (28), Stal nierdzewna (6)
BL1 | PIĘTRO 3 | Stal konstrukcyjna (29), Stal nierdzewna (9)
2 x BL1 | PIĘTRO 3 | Stal konstrukcyjna (20), Stal nierdzewna (3)
BL1 | PIĘTRO 3 | Stal konstrukcyjna (23), Stal nierdzewna (3)
BL1 | PIĘTRO 3 | Stal konstrukcyjna (18), Stal nierdzewna (3)
2 x BL1 | PIĘTRO 4 | Szkło struktualne (2), Profile aluminiowe (2)
12 x BL1 | PIĘTRO 4 | Szkło struktualne, Profile aluminiowe
2 x BL1 | PIĘTRO 4 | Stal nierdzewna (3)
BL1 | PIĘTRO 4 | Stal konstrukcyjna (25), Stal nierdzewna (3)
4 x BL1 | PIĘTRO 4 | Szkło struktualne (3), Profile aluminiowe (3)
BL1 | PIĘTRO 4 | Stal konstrukcyjna (27), Stal nierdzewna (3)
2 x BL1 | PIĘTRO 4 | Stal konstrukcyjna (41), Stal nierdzewna (9)
BL1 | PIĘTRO 4 | Stal konstrukcyjna (28), Stal nierdzewna (6)
2 x BL1 | PIĘTRO 4 | Stal konstrukcyjna (20), Stal nierdzewna (3)
BL1 | PIĘTRO 4 | Stal konstrukcyjna (14), Stal nierdzewna (3)
BL1 | PIĘTRO 4 | Stal konstrukcyjna (25), Stal nierdzewna (6)
BL1 | PIĘTRO 4 | Stal konstrukcyjna (15), Stal nierdzewna (3)
BL1 | PIĘTRO 4 | Stal konstrukcyjna (24), Stal nierdzewna (6)
BL1 | PIĘTRO 4 | Stal konstrukcyjna (16), Stal nierdzewna (3)
36 x BL1 | ANTRESOLA - KOND. TECHNICZNA | Szkło struktualne, Profile aluminiowe
8 x BL1 | ANTRESOLA - KOND. TECHNICZNA | Szkło struktualne (2), Profile aluminiowe (2)
4 x BL1 | ANTRESOLA - KOND. TECHNICZNA | Szkło struktualne (3), Profile aluminiowe (3)
BL1 | ANTRESOLA - KOND. TECHNICZNA | Szkło struktualne (7), Profile aluminiowe (7)
BL1 | DACH | Szkło struktualne (8), Profile aluminiowe (8)

# IfcSlab: 500-PS ---- PODŁOGI STROPY ----------------- 300 (4)
In: GARAZ
Type - PredefinedType: ROOF
Material: ---- OKŁADZINY WEW -----------, Beton konstrukcyjny B25
Pset_ConcreteElementGeneral - FireRating: -; ConstructionType: -
Pset_SlabCommon - AcousticRating: 0,00; FireRating: -; ThermalTransmittance: 0; LoadBearing: no; IsExternal: yes
Pset_FireRatingProperties - FireResistanceRating: -
AC_Pset_RenovationAndPhasing - Renovation Status: New

# IfcSlab: 501-P2 STROP PARTER 480 (4)
In: PARTER
Type - PredefinedType: FLOOR
Material: Płytki podłogowe, Klej elastyczny, Beton, Płyty styropianowe EPS PODŁOGA, Beton konstrukcyjny 01, Termoizolacja WEŁNA SKALNA
Pset_ConcreteElementGeneral - FireRating: -; ConstructionType: -
Pset_SlabCommon - AcousticRating: 0,00; FireRating: -; ThermalTransmittance: 0; LoadBearing: yes; IsExternal: no
Pset_FireRatingProperties - FireResistanceRating: -
AC_Pset_RenovationAndPhasing - Renovation Status: New

# IfcSlab: 501-P3 STROP PARTER 350, P3.1
In: PARTER
Type - PredefinedType: FLOOR
Material: Beton konstrukcyjny 01, Termoizolacja WEŁNA SKALNA
Pset_ConcreteElementGeneral - FireRating: -; ConstructionType: -
Pset_SlabCommon - AcousticRating: 0,00; FireRating: -; ThermalTransmittance: 0; LoadBearing: yes; IsExternal: no
Pset_FireRatingProperties - FireResistanceRating: -
AC_Pset_RenovationAndPhasing - Renovation Status: New

# IfcSlab: 501-PS STROP DACH 455, P2
In: DACH
Type - PredefinedType: FLOOR
Material: Płyty styropianowe EPS PODŁOGA, Paroizolacja, STROP monolityczny
Pset_ConcreteElementGeneral - FireRating: -; ConstructionType: -
Pset_SlabCommon - AcousticRating: 0,00; FireRating: -; ThermalTransmittance: 0; LoadBearing: yes; IsExternal: no
Pset_FireRatingProperties - FireResistanceRating: -
AC_Pset_RenovationAndPhasing - Renovation Status: New

# IfcSlab: 502-PS STROP POWTARZALNA 360 (15)
Type - PredefinedType: FLOOR
Pset_ConcreteElementGeneral - FireRating: -; ConstructionType: -
Pset_SlabCommon - AcousticRating: 0,00; FireRating: -; ThermalTransmittance: 0; LoadBearing: yes; IsExternal: no
Pset_FireRatingProperties - FireResistanceRating: -
AC_Pset_RenovationAndPhasing - Renovation Status: New
Name | In | Material
P4 | PIĘTRO 1 | Wylewka, Płyty styropianowe EPS PODŁOGA, STROP monolityczny
2 x P4 | PIĘTRO 1 | Płytki podłogowe, Klej elastyczny, Wylewka, Płyty styropianowe EPS PODŁOGA, STROP monolityczny
P1 | PIĘTRO 1 | Płytki podłogowe, Klej elastyczny, Wylewka, Płyty styropianowe EPS PODŁOGA, STROP monolityczny
P4 | PIĘTRO 2 | Wylewka, Płyty styropianowe EPS PODŁOGA, STROP monolityczny
3 x P4 | PIĘTRO 2 | Płytki podłogowe, Klej elastyczny, Wylewka, Płyty styropianowe EPS PODŁOGA, STROP monolityczny
3 x P4 | PIĘTRO 3 | Płytki podłogowe, Klej elastyczny, Wylewka, Płyty styropianowe EPS PODŁOGA, STROP monolityczny
P4 | PIĘTRO 3 | STROP monolityczny
3 x P4 | PIĘTRO 4 | Płytki podłogowe, Klej elastyczny, Wylewka, Płyty styropianowe EPS PODŁOGA, STROP monolityczny

# IfcSlab: 503-PS STROP ANTRESOLA 450 (7)
In: ANTRESOLA - KOND. TECHNICZNA
Type - PredefinedType: FLOOR
Material: Płytki podłogowe, Klej elastyczny, Wylewka, Płyty styropianowe EPS PODŁOGA, STROP monolityczny
Pset_ConcreteElementGeneral - FireRating: -; ConstructionType: -
Pset_SlabCommon - AcousticRating: 0,00; FireRating: -; ThermalTransmittance: 0; LoadBearing: yes; IsExternal: no
Pset_FireRatingProperties - FireResistanceRating: -
AC_Pset_RenovationAndPhasing - Renovation Status: New

# IfcSlab: 504-PS STROP DACH PŁASKI 205 (7)
Type - PredefinedType: FLOOR
Material: Membrana hydroizolacyjna, STROP monolityczny
Pset_ConcreteElementGeneral - FireRating: -; ConstructionType: -
Pset_SlabCommon - AcousticRating: 0,00; FireRating: -; ThermalTransmittance: 0; LoadBearing: yes; IsExternal: no
Pset_FireRatingProperties - FireResistanceRating: -
AC_Pset_RenovationAndPhasing - Renovation Status: New
Name | In
2 x P10 | ANTRESOLA - KOND. TECHNICZNA
5 x P6 | DACH

# IfcSlab: 509-PS STROP DACH BALAST 560 (43)
Type - PredefinedType: ROOF
Pset_ConcreteElementGeneral - FireRating: -; ConstructionType: -
Pset_SlabCommon - AcousticRating: 0,00; FireRating: -; ThermalTransmittance: 0; LoadBearing: no; IsExternal: yes
Pset_FireRatingProperties - FireResistanceRating: -
AC_Pset_RenovationAndPhasing - Renovation Status: New
Name | In | Material
12 x DA3 | ANTRESOLA - KOND. TECHNICZNA | Okładzina kamienna, Żwir, Membrana hydroizolacyjna, Termoizolacja PIR (2)
29 x DA3 | DACH | Okładzina kamienna, Żwir, Membrana hydroizolacyjna, Termoizolacja PIR (2)
2 x DA3 | DACH | Okładzina kamienna 20 mm, Żwir 80 mm, Membrana hydroizolacyjna 10 mm, Termoizolacja PIR 150 mm, Termoizolacja PIR 300 mm

# IfcSlab: 509-PS STROP DACH PŁASKI PIR 355 (3)
In: PARTER
Type - PredefinedType: FLOOR
Material: Termoizolacja PIR, Paroizolacja, Beton konstrukcyjny B25
Pset_ConcreteElementGeneral - FireRating: -; ConstructionType: -
Pset_SlabCommon - AcousticRating: 0,00; FireRating: -; ThermalTransmittance: 0; LoadBearing: yes; IsExternal: no
Pset_FireRatingProperties - FireResistanceRating: -
AC_Pset_RenovationAndPhasing - Renovation Status: New

# IfcSlab: 541-PS PODŁOGA NA GRUNCIE 1000, P1
In: GARAZ
Type - PredefinedType: FLOOR
Material: Beton, Beton konstrukcyjny 01, Płyty styropianowe twarde HIGH-PRIORITY, Żwir
Pset_ConcreteElementGeneral - FireRating: -; ConstructionType: -
Pset_SlabCommon - AcousticRating: 0,00; FireRating: -; ThermalTransmittance: 0; LoadBearing: yes; IsExternal: no
Pset_FireRatingProperties - FireResistanceRating: -
AC_Pset_RenovationAndPhasing - Renovation Status: New

# IfcSlab: 541-PS PODŁOGA NA GRUNCIE WINDA 700, P3
In: GARAZ
Type - PredefinedType: FLOOR
Material: Beton konstrukcyjny 01, Płyty styropianowe twarde, Żwir
Pset_ConcreteElementGeneral - FireRating: -; ConstructionType: -
Pset_SlabCommon - AcousticRating: 0,00; FireRating: -; ThermalTransmittance: 0; LoadBearing: yes; IsExternal: no
Pset_FireRatingProperties - FireResistanceRating: -
AC_Pset_RenovationAndPhasing - Renovation Status: New

# IfcSlab: 541-PS PODŁOGA TECHN. KANAŁY 400, P1
In: GARAZ
Type - PredefinedType: FLOOR
Material: Beton konstrukcyjny 01, Płyty styropianowe twarde, Żwir
Pset_ConcreteElementGeneral - FireRating: -; ConstructionType: -
Pset_SlabCommon - AcousticRating: 0,00; FireRating: -; ThermalTransmittance: 0; LoadBearing: yes; IsExternal: no
Pset_FireRatingProperties - FireResistanceRating: -
AC_Pset_RenovationAndPhasing - Renovation Status: New

# IfcSlab: 611-DS Wykonczenie teren komunikacja 480 (5)
In: PARTER
Type - PredefinedType: FLOOR
Material: Bloczki betonowe, Piasek, Membrana hydroizolacyjna (2), Polistyren ekstrudowany, Beton
Pset_ConcreteElementGeneral - FireRating: -; ConstructionType: -
Pset_SlabCommon - AcousticRating: 0,00; FireRating: -; ThermalTransmittance: 0; LoadBearing: yes; IsExternal: no
Pset_FireRatingProperties - FireResistanceRating: -
AC_Pset_RenovationAndPhasing - Renovation Status: New
Name
3 x P2
P3
P3.2

# IfcSlab: Balkony na FAT 2 450 (4)
In: ANTRESOLA - KOND. TECHNICZNA
Type - PredefinedType: FLOOR
Material: Płytki okładzinowe, Wylewka, Płyty styropianowe twarde, Membrana przeciwwilgociowa, Beton konstrukcyjny B25, Tynk zewnętrzny
Pset_ConcreteElementGeneral - FireRating: -; ConstructionType: -
Pset_SlabCommon - AcousticRating: 0,00; FireRating: -; ThermalTransmittance: 0; LoadBearing: yes; IsExternal: no
Pset_FireRatingProperties - FireResistanceRating: -
AC_Pset_RenovationAndPhasing - Renovation Status: New
Name
2 x P9
2 x P3

# IfcSlab: Balkony na HALFENACH 330 (31)
Type - PredefinedType: FLOOR
Material: Płytki okładzinowe, Pustka powietrzna, Membrana przeciwwilgociowa, Beton konstrukcyjny B25, Laminat
Pset_ConcreteElementGeneral - FireRating: -; ConstructionType: -
Pset_SlabCommon - AcousticRating: 0,00; FireRating: -; ThermalTransmittance: 0; LoadBearing: yes; IsExternal: no
Pset_FireRatingProperties - FireResistanceRating: -
AC_Pset_RenovationAndPhasing - Renovation Status: New
Name | In
3 x P3 | PIĘTRO 1
2 x P8 | PIĘTRO 1
6 x P3 | PIĘTRO 2
2 x P8 | PIĘTRO 2
6 x P3 | PIĘTRO 3
2 x P8 | PIĘTRO 3
6 x P3 | PIĘTRO 4
2 x P8 | PIĘTRO 4
2 x P3 | ANTRESOLA - KOND. TECHNICZNA

# IfcSlab: Balkony na HALFENACH FAT 480 (5)
Type - PredefinedType: FLOOR
Material: Płytki okładzinowe, Beton, Płyty styropianowe twarde, Membrana przeciwwilgociowa, Beton konstrukcyjny B25, Pustka powietrzna, Laminat
Pset_ConcreteElementGeneral - FireRating: -; ConstructionType: -
Pset_SlabCommon - AcousticRating: 0,00; FireRating: -; ThermalTransmittance: 0; LoadBearing: yes; IsExternal: no
Pset_FireRatingProperties - FireResistanceRating: -
AC_Pset_RenovationAndPhasing - Renovation Status: New
Name | In
3 x P3 | PIĘTRO 1
2 x P9 | ANTRESOLA - KOND. TECHNICZNA

# IfcSlab: Balkony na HALFENACH SuperFAT 450 (6)
In: DACH
Type - PredefinedType: FLOOR
Material: Membrana przeciwwilgociowa, Beton konstrukcyjny B25, Pustka powietrzna, Laminat
Pset_ConcreteElementGeneral - FireRating: -; ConstructionType: -
Pset_SlabCommon - AcousticRating: 0,00; FireRating: -; ThermalTransmittance: 0; LoadBearing: yes; IsExternal: no
Pset_FireRatingProperties - FireResistanceRating: -
AC_Pset_RenovationAndPhasing - Renovation Status: New
Name
4 x P7'
2 x P3

# IfcSlab: Beton konstrukcyjny 01 300, P3.1
In: PARTER
Type - PredefinedType: FLOOR
Material: Beton konstrukcyjny 01
Pset_ConcreteElementGeneral - FireRating: -; ConstructionType: -
Pset_SlabCommon - AcousticRating: 0,00; FireRating: -; ThermalTransmittance: 0; LoadBearing: yes; IsExternal: no
Pset_FireRatingProperties - FireResistanceRating: -
AC_Pset_RenovationAndPhasing - Renovation Status: New

# IfcSlab: Beton konstrukcyjny B25 120 (54)
Type - PredefinedType: FLOOR
Material: Beton konstrukcyjny B25
Pset_ConcreteElementGeneral - FireRating: -; ConstructionType: -
Pset_SlabCommon - AcousticRating: 0,00; FireRating: -; ThermalTransmittance: 0; LoadBearing: yes; IsExternal: no
Pset_FireRatingProperties - FireResistanceRating: -
AC_Pset_RenovationAndPhasing - Renovation Status: New
Name | In
6 x P3 | ANTRESOLA - KOND. TECHNICZNA
48 x P3 | DACH

# IfcSlab: Beton konstrukcyjny B25 140, P3
In: DACH
Type - PredefinedType: FLOOR
Material: Beton konstrukcyjny B25
Pset_ConcreteElementGeneral - FireRating: -; ConstructionType: -
Pset_SlabCommon - AcousticRating: 0,00; FireRating: -; ThermalTransmittance: 0; LoadBearing: yes; IsExternal: no
Pset_FireRatingProperties - FireResistanceRating: -
AC_Pset_RenovationAndPhasing - Renovation Status: New

# IfcSlab: Beton konstrukcyjny B25 200 (3)
Type - PredefinedType: FLOOR
Material: Beton konstrukcyjny B25
Pset_ConcreteElementGeneral - FireRating: -; ConstructionType: -
Pset_SlabCommon - AcousticRating: 0,00; FireRating: -; ThermalTransmittance: 0; LoadBearing: yes; IsExternal: no
Pset_FireRatingProperties - FireResistanceRating: -
AC_Pset_RenovationAndPhasing - Renovation Status: New
Name | In
P2 | GARAZ
2 x P10 | ANTRESOLA - KOND. TECHNICZNA

# IfcSlab: Beton konstrukcyjny B25 220 (2)
In: DACH
Type - PredefinedType: FLOOR
Material: Beton konstrukcyjny B25
Pset_ConcreteElementGeneral - FireRating: -; ConstructionType: -
Pset_SlabCommon - AcousticRating: 0,00; FireRating: -; ThermalTransmittance: 0; LoadBearing: yes; IsExternal: no
Pset_FireRatingProperties - FireResistanceRating: -
AC_Pset_RenovationAndPhasing - Renovation Status: New

# IfcSlab: Beton konstrukcyjny B25 300, P3.1
In: PARTER
Type - PredefinedType: FLOOR
Material: Beton konstrukcyjny B25
Pset_ConcreteElementGeneral - FireRating: -; ConstructionType: -
Pset_SlabCommon - AcousticRating: 0,00; FireRating: -; ThermalTransmittance: 0; LoadBearing: yes; IsExternal: no
Pset_FireRatingProperties - FireResistanceRating: -
AC_Pset_RenovationAndPhasing - Renovation Status: New

# IfcSlab: Beton konstrukcyjny B25 450 (2)
In: DACH
Type - PredefinedType: FLOOR
Material: Beton konstrukcyjny B25
Pset_ConcreteElementGeneral - FireRating: -; ConstructionType: -
Pset_SlabCommon - AcousticRating: 0,00; FireRating: -; ThermalTransmittance: 0; LoadBearing: yes; IsExternal: no
Pset_FireRatingProperties - FireResistanceRating: -
AC_Pset_RenovationAndPhasing - Renovation Status: New

# IfcSlab: Drewno podłogowe 30, P2
In: DACH
Type - PredefinedType: FLOOR
Material: Drewno podłogowe 30 mm
Pset_ConcreteElementGeneral - FireRating: -; ConstructionType: -
Pset_SlabCommon - AcousticRating: 0,00; FireRating: -; ThermalTransmittance: 0; LoadBearing: yes; IsExternal: no
Pset_FireRatingProperties - FireResistanceRating: -
AC_Pset_RenovationAndPhasing - Renovation Status: New

# IfcSlab: Kostka brukowa 80 (3)
In: PARTER
Type - PredefinedType: FLOOR
Material: Kostka brukowa
Pset_ConcreteElementGeneral - FireRating: -; ConstructionType: -
Pset_SlabCommon - AcousticRating: 0,00; FireRating: -; ThermalTransmittance: 0; LoadBearing: yes; IsExternal: no
Pset_FireRatingProperties - FireResistanceRating: -
AC_Pset_RenovationAndPhasing - Renovation Status: New

# IfcSlab: Laminat 140 (2)
In: PARTER
Type - PredefinedType: FLOOR
Material: Laminat
Pset_ConcreteElementGeneral - FireRating: -; ConstructionType: -
Pset_SlabCommon - AcousticRating: 0,00; FireRating: -; ThermalTransmittance: 0; LoadBearing: yes; IsExternal: no
Pset_FireRatingProperties - FireResistanceRating: -
AC_Pset_RenovationAndPhasing - Renovation Status: New

# IfcSlab: Laminat 150 (6)
In: PIĘTRO 4
Type - PredefinedType: FLOOR
Material: Laminat
Pset_ConcreteElementGeneral - FireRating: -; ConstructionType: -
Pset_SlabCommon - AcousticRating: 0,00; FireRating: -; ThermalTransmittance: 0; LoadBearing: yes; IsExternal: no
Pset_FireRatingProperties - FireResistanceRating: -
AC_Pset_RenovationAndPhasing - Renovation Status: New

# IfcSlab: Laminat 25, P6
In: PARTER
Type - PredefinedType: FLOOR
Material: Laminat
Pset_ConcreteElementGeneral - FireRating: -; ConstructionType: -
Pset_SlabCommon - AcousticRating: 0,00; FireRating: -; ThermalTransmittance: 0; LoadBearing: no; IsExternal: no
Pset_FireRatingProperties - FireResistanceRating: -
AC_Pset_RenovationAndPhasing - Renovation Status: New

# IfcSlab: Laminat 80 (2)
In: DACH
Type - PredefinedType: FLOOR
Material: Laminat
Pset_ConcreteElementGeneral - FireRating: -; ConstructionType: -
Pset_SlabCommon - AcousticRating: 0,00; FireRating: -; ThermalTransmittance: 0; LoadBearing: yes; IsExternal: no
Pset_FireRatingProperties - FireResistanceRating: -
AC_Pset_RenovationAndPhasing - Renovation Status: New

# IfcSlab: Strop techn. ZEWN. 360, P2
In: DACH
Type - PredefinedType: FLOOR
Material: Membrana przeciwwilgociowa (2), Płyty styropianowe twarde, Beton konstrukcyjny B25
Pset_ConcreteElementGeneral - FireRating: -; ConstructionType: -
Pset_SlabCommon - AcousticRating: 0,00; FireRating: -; ThermalTransmittance: 0; LoadBearing: yes; IsExternal: no
Pset_FireRatingProperties - FireResistanceRating: -
AC_Pset_RenovationAndPhasing - Renovation Status: New

# IfcSlab: Szkło struktualne 900, P6
In: PARTER
Type - PredefinedType: FLOOR
Material: Szkło struktualne 900 mm
Pset_ConcreteElementGeneral - FireRating: -; ConstructionType: -
Pset_SlabCommon - AcousticRating: 0,00; FireRating: -; ThermalTransmittance: 0; LoadBearing: no; IsExternal: no
Pset_FireRatingProperties - FireResistanceRating: -
AC_Pset_RenovationAndPhasing - Renovation Status: New

# IfcSlab: Tarasy kond.5 440 (6)
In: ANTRESOLA - KOND. TECHNICZNA
Type - PredefinedType: FLOOR
Material: Płytki okładzinowe, Wylewka, Płyty styropianowe twarde, Membrana przeciwwilgociowa, Beton konstrukcyjny B25
Pset_ConcreteElementGeneral - FireRating: -; ConstructionType: -
Pset_SlabCommon - AcousticRating: 0,00; FireRating: -; ThermalTransmittance: 0; LoadBearing: yes; IsExternal: no
Pset_FireRatingProperties - FireResistanceRating: -
AC_Pset_RenovationAndPhasing - Renovation Status: New
Name
4 x P10
2 x P9

# IfcSlab: Wełna ELEW wysoki priorytet 240, P2
In: PARTER
Type - PredefinedType: FLOOR
Material: Wełna ELEW wysoki priorytet
Pset_ConcreteElementGeneral - FireRating: -; ConstructionType: -
Pset_SlabCommon - AcousticRating: 0,00; FireRating: -; ThermalTransmittance: 0; LoadBearing: yes; IsExternal: no
Pset_FireRatingProperties - FireResistanceRating: -
AC_Pset_RenovationAndPhasing - Renovation Status: New

# IfcStair (27)
Pset_ConcreteElementGeneral - FireRating: -; ConstructionType: -
Pset_StairCommon - RequiredHeadroom: 2200 mm; FireRating: -; HasNonSkidSurface: no; IsExternal: no
Pset_FireRatingProperties - FireResistanceRating: -
AC_Pset_RenovationAndPhasing - Renovation Status: New
Name | In | Material | NumberOfRiser = NumberOfTreads | RiserHeight (mm)
26 x SCH2 | PIĘTRO 4 | Beton konstrukcyjny B25, Drewno konstrukcyjne (16) | 16 | 193.125
SCH3 | ANTRESOLA - KOND. TECHNICZNA | Beton konstrukcyjny B25 (3), Drewno konstrukcyjne (19) | 19 | 174.737

# IfcWall: Zakończenie zamknięte 23 (54)
Material: Tynk zewnętrzny
Pset_ConcreteElementGeneral - FireRating: -; ConstructionType: -
Pset_WallCommon - AcousticRating: 0,00; FireRating: -; ThermalTransmittance: 0
Pset_FireRatingProperties - FireResistanceRating: -
AC_Pset_RenovationAndPhasing - Renovation Status: New
Name | In
12 x ZS1 | PIĘTRO 1
12 x ZS1 | PIĘTRO 2
12 x ZS1 | PIĘTRO 3
12 x ZS1 | PIĘTRO 4
6 x ZS1 | ANTRESOLA - KOND. TECHNICZNA
